# Generated by FakeRAM 2.0 (routing-friendly)
VERSION 5.7 ;
BUSBITCHARS "[]" ;
PROPERTYDEFINITIONS
  MACRO width INTEGER ;
  MACRO depth INTEGER ;
  MACRO banks INTEGER ;
END PROPERTYDEFINITIONS
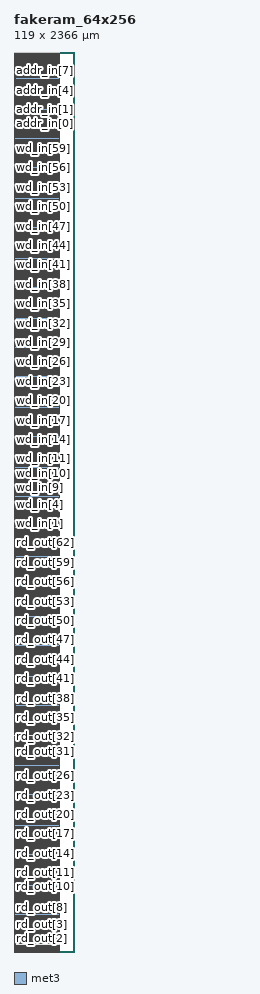
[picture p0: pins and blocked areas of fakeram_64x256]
MACRO fakeram_64x256
  PROPERTY width 64 ;
  PROPERTY depth 256 ;
  PROPERTY banks 1 ;
  FOREIGN fakeram_64x256 0 0 ;
  SYMMETRY X Y R90 ;
  SIZE 119.000 BY 2366.000 ;
  CLASS BLOCK ;
  PIN rd_out[0]
    DIRECTION OUTPUT ;
    USE SIGNAL ;
    PORT
      LAYER met3 ;
      RECT 1.000 0.680 3.000 1.380 ;
    END
    PORT
      LAYER met3 ;
      RECT 1.000 0.330 4.000 1.730 ;
    END
  END rd_out[0]
  PIN rd_out[1]
    DIRECTION OUTPUT ;
    USE SIGNAL ;
    PORT
      LAYER met3 ;
      RECT 1.000 17.680 3.000 18.380 ;
    END
    PORT
      LAYER met3 ;
      RECT 1.000 17.330 4.000 18.730 ;
    END
  END rd_out[1]
  PIN rd_out[2]
    DIRECTION OUTPUT ;
    USE SIGNAL ;
    PORT
      LAYER met3 ;
      RECT 1.000 34.680 3.000 35.380 ;
    END
    PORT
      LAYER met3 ;
      RECT 1.000 34.330 4.000 35.730 ;
    END
  END rd_out[2]
  PIN rd_out[3]
    DIRECTION OUTPUT ;
    USE SIGNAL ;
    PORT
      LAYER met3 ;
      RECT 1.000 51.680 3.000 52.380 ;
    END
    PORT
      LAYER met3 ;
      RECT 1.000 51.330 4.000 52.730 ;
    END
  END rd_out[3]
  PIN rd_out[4]
    DIRECTION OUTPUT ;
    USE SIGNAL ;
    PORT
      LAYER met3 ;
      RECT 1.000 68.680 3.000 69.380 ;
    END
    PORT
      LAYER met3 ;
      RECT 1.000 68.330 4.000 69.730 ;
    END
  END rd_out[4]
  PIN rd_out[5]
    DIRECTION OUTPUT ;
    USE SIGNAL ;
    PORT
      LAYER met3 ;
      RECT 1.000 85.680 3.000 86.380 ;
    END
    PORT
      LAYER met3 ;
      RECT 1.000 85.330 4.000 86.730 ;
    END
  END rd_out[5]
  PIN rd_out[6]
    DIRECTION OUTPUT ;
    USE SIGNAL ;
    PORT
      LAYER met3 ;
      RECT 1.000 102.680 3.000 103.380 ;
    END
    PORT
      LAYER met3 ;
      RECT 1.000 102.330 4.000 103.730 ;
    END
  END rd_out[6]
  PIN rd_out[7]
    DIRECTION OUTPUT ;
    USE SIGNAL ;
    PORT
      LAYER met3 ;
      RECT 1.000 119.680 3.000 120.380 ;
    END
    PORT
      LAYER met3 ;
      RECT 1.000 119.330 4.000 120.730 ;
    END
  END rd_out[7]
  PIN rd_out[8]
    DIRECTION OUTPUT ;
    USE SIGNAL ;
    PORT
      LAYER met3 ;
      RECT 1.000 136.680 3.000 137.380 ;
    END
    PORT
      LAYER met3 ;
      RECT 1.000 136.330 4.000 137.730 ;
    END
  END rd_out[8]
  PIN rd_out[9]
    DIRECTION OUTPUT ;
    USE SIGNAL ;
    PORT
      LAYER met3 ;
      RECT 1.000 153.680 3.000 154.380 ;
    END
    PORT
      LAYER met3 ;
      RECT 1.000 153.330 4.000 154.730 ;
    END
  END rd_out[9]
  PIN rd_out[10]
    DIRECTION OUTPUT ;
    USE SIGNAL ;
    PORT
      LAYER met3 ;
      RECT 1.000 170.680 3.000 171.380 ;
    END
    PORT
      LAYER met3 ;
      RECT 1.000 170.330 4.000 171.730 ;
    END
  END rd_out[10]
  PIN rd_out[11]
    DIRECTION OUTPUT ;
    USE SIGNAL ;
    PORT
      LAYER met3 ;
      RECT 1.000 187.680 3.000 188.380 ;
    END
    PORT
      LAYER met3 ;
      RECT 1.000 187.330 4.000 188.730 ;
    END
  END rd_out[11]
  PIN rd_out[12]
    DIRECTION OUTPUT ;
    USE SIGNAL ;
    PORT
      LAYER met3 ;
      RECT 1.000 204.680 3.000 205.380 ;
    END
    PORT
      LAYER met3 ;
      RECT 1.000 204.330 4.000 205.730 ;
    END
  END rd_out[12]
  PIN rd_out[13]
    DIRECTION OUTPUT ;
    USE SIGNAL ;
    PORT
      LAYER met3 ;
      RECT 1.000 221.680 3.000 222.380 ;
    END
    PORT
      LAYER met3 ;
      RECT 1.000 221.330 4.000 222.730 ;
    END
  END rd_out[13]
  PIN rd_out[14]
    DIRECTION OUTPUT ;
    USE SIGNAL ;
    PORT
      LAYER met3 ;
      RECT 1.000 238.680 3.000 239.380 ;
    END
    PORT
      LAYER met3 ;
      RECT 1.000 238.330 4.000 239.730 ;
    END
  END rd_out[14]
  PIN rd_out[15]
    DIRECTION OUTPUT ;
    USE SIGNAL ;
    PORT
      LAYER met3 ;
      RECT 1.000 255.680 3.000 256.380 ;
    END
    PORT
      LAYER met3 ;
      RECT 1.000 255.330 4.000 256.730 ;
    END
  END rd_out[15]
  PIN rd_out[16]
    DIRECTION OUTPUT ;
    USE SIGNAL ;
    PORT
      LAYER met3 ;
      RECT 1.000 272.680 3.000 273.380 ;
    END
    PORT
      LAYER met3 ;
      RECT 1.000 272.330 4.000 273.730 ;
    END
  END rd_out[16]
  PIN rd_out[17]
    DIRECTION OUTPUT ;
    USE SIGNAL ;
    PORT
      LAYER met3 ;
      RECT 1.000 289.680 3.000 290.380 ;
    END
    PORT
      LAYER met3 ;
      RECT 1.000 289.330 4.000 290.730 ;
    END
  END rd_out[17]
  PIN rd_out[18]
    DIRECTION OUTPUT ;
    USE SIGNAL ;
    PORT
      LAYER met3 ;
      RECT 1.000 306.680 3.000 307.380 ;
    END
    PORT
      LAYER met3 ;
      RECT 1.000 306.330 4.000 307.730 ;
    END
  END rd_out[18]
  PIN rd_out[19]
    DIRECTION OUTPUT ;
    USE SIGNAL ;
    PORT
      LAYER met3 ;
      RECT 1.000 323.680 3.000 324.380 ;
    END
    PORT
      LAYER met3 ;
      RECT 1.000 323.330 4.000 324.730 ;
    END
  END rd_out[19]
  PIN rd_out[20]
    DIRECTION OUTPUT ;
    USE SIGNAL ;
    PORT
      LAYER met3 ;
      RECT 1.000 340.680 3.000 341.380 ;
    END
    PORT
      LAYER met3 ;
      RECT 1.000 340.330 4.000 341.730 ;
    END
  END rd_out[20]
  PIN rd_out[21]
    DIRECTION OUTPUT ;
    USE SIGNAL ;
    PORT
      LAYER met3 ;
      RECT 1.000 357.680 3.000 358.380 ;
    END
    PORT
      LAYER met3 ;
      RECT 1.000 357.330 4.000 358.730 ;
    END
  END rd_out[21]
  PIN rd_out[22]
    DIRECTION OUTPUT ;
    USE SIGNAL ;
    PORT
      LAYER met3 ;
      RECT 1.000 374.680 3.000 375.380 ;
    END
    PORT
      LAYER met3 ;
      RECT 1.000 374.330 4.000 375.730 ;
    END
  END rd_out[22]
  PIN rd_out[23]
    DIRECTION OUTPUT ;
    USE SIGNAL ;
    PORT
      LAYER met3 ;
      RECT 1.000 391.680 3.000 392.380 ;
    END
    PORT
      LAYER met3 ;
      RECT 1.000 391.330 4.000 392.730 ;
    END
  END rd_out[23]
  PIN rd_out[24]
    DIRECTION OUTPUT ;
    USE SIGNAL ;
    PORT
      LAYER met3 ;
      RECT 1.000 408.680 3.000 409.380 ;
    END
    PORT
      LAYER met3 ;
      RECT 1.000 408.330 4.000 409.730 ;
    END
  END rd_out[24]
  PIN rd_out[25]
    DIRECTION OUTPUT ;
    USE SIGNAL ;
    PORT
      LAYER met3 ;
      RECT 1.000 425.680 3.000 426.380 ;
    END
    PORT
      LAYER met3 ;
      RECT 1.000 425.330 4.000 426.730 ;
    END
  END rd_out[25]
  PIN rd_out[26]
    DIRECTION OUTPUT ;
    USE SIGNAL ;
    PORT
      LAYER met3 ;
      RECT 1.000 442.680 3.000 443.380 ;
    END
    PORT
      LAYER met3 ;
      RECT 1.000 442.330 4.000 443.730 ;
    END
  END rd_out[26]
  PIN rd_out[27]
    DIRECTION OUTPUT ;
    USE SIGNAL ;
    PORT
      LAYER met3 ;
      RECT 1.000 459.680 3.000 460.380 ;
    END
    PORT
      LAYER met3 ;
      RECT 1.000 459.330 4.000 460.730 ;
    END
  END rd_out[27]
  PIN rd_out[28]
    DIRECTION OUTPUT ;
    USE SIGNAL ;
    PORT
      LAYER met3 ;
      RECT 1.000 476.680 3.000 477.380 ;
    END
    PORT
      LAYER met3 ;
      RECT 1.000 476.330 4.000 477.730 ;
    END
  END rd_out[28]
  PIN rd_out[29]
    DIRECTION OUTPUT ;
    USE SIGNAL ;
    PORT
      LAYER met3 ;
      RECT 1.000 493.680 3.000 494.380 ;
    END
    PORT
      LAYER met3 ;
      RECT 1.000 493.330 4.000 494.730 ;
    END
  END rd_out[29]
  PIN rd_out[30]
    DIRECTION OUTPUT ;
    USE SIGNAL ;
    PORT
      LAYER met3 ;
      RECT 1.000 510.680 3.000 511.380 ;
    END
    PORT
      LAYER met3 ;
      RECT 1.000 510.330 4.000 511.730 ;
    END
  END rd_out[30]
  PIN rd_out[31]
    DIRECTION OUTPUT ;
    USE SIGNAL ;
    PORT
      LAYER met3 ;
      RECT 1.000 527.680 3.000 528.380 ;
    END
    PORT
      LAYER met3 ;
      RECT 1.000 527.330 4.000 528.730 ;
    END
  END rd_out[31]
  PIN rd_out[32]
    DIRECTION OUTPUT ;
    USE SIGNAL ;
    PORT
      LAYER met3 ;
      RECT 1.000 544.680 3.000 545.380 ;
    END
    PORT
      LAYER met3 ;
      RECT 1.000 544.330 4.000 545.730 ;
    END
  END rd_out[32]
  PIN rd_out[33]
    DIRECTION OUTPUT ;
    USE SIGNAL ;
    PORT
      LAYER met3 ;
      RECT 1.000 561.680 3.000 562.380 ;
    END
    PORT
      LAYER met3 ;
      RECT 1.000 561.330 4.000 562.730 ;
    END
  END rd_out[33]
  PIN rd_out[34]
    DIRECTION OUTPUT ;
    USE SIGNAL ;
    PORT
      LAYER met3 ;
      RECT 1.000 578.680 3.000 579.380 ;
    END
    PORT
      LAYER met3 ;
      RECT 1.000 578.330 4.000 579.730 ;
    END
  END rd_out[34]
  PIN rd_out[35]
    DIRECTION OUTPUT ;
    USE SIGNAL ;
    PORT
      LAYER met3 ;
      RECT 1.000 595.680 3.000 596.380 ;
    END
    PORT
      LAYER met3 ;
      RECT 1.000 595.330 4.000 596.730 ;
    END
  END rd_out[35]
  PIN rd_out[36]
    DIRECTION OUTPUT ;
    USE SIGNAL ;
    PORT
      LAYER met3 ;
      RECT 1.000 612.680 3.000 613.380 ;
    END
    PORT
      LAYER met3 ;
      RECT 1.000 612.330 4.000 613.730 ;
    END
  END rd_out[36]
  PIN rd_out[37]
    DIRECTION OUTPUT ;
    USE SIGNAL ;
    PORT
      LAYER met3 ;
      RECT 1.000 629.680 3.000 630.380 ;
    END
    PORT
      LAYER met3 ;
      RECT 1.000 629.330 4.000 630.730 ;
    END
  END rd_out[37]
  PIN rd_out[38]
    DIRECTION OUTPUT ;
    USE SIGNAL ;
    PORT
      LAYER met3 ;
      RECT 1.000 646.680 3.000 647.380 ;
    END
    PORT
      LAYER met3 ;
      RECT 1.000 646.330 4.000 647.730 ;
    END
  END rd_out[38]
  PIN rd_out[39]
    DIRECTION OUTPUT ;
    USE SIGNAL ;
    PORT
      LAYER met3 ;
      RECT 1.000 663.680 3.000 664.380 ;
    END
    PORT
      LAYER met3 ;
      RECT 1.000 663.330 4.000 664.730 ;
    END
  END rd_out[39]
  PIN rd_out[40]
    DIRECTION OUTPUT ;
    USE SIGNAL ;
    PORT
      LAYER met3 ;
      RECT 1.000 680.680 3.000 681.380 ;
    END
    PORT
      LAYER met3 ;
      RECT 1.000 680.330 4.000 681.730 ;
    END
  END rd_out[40]
  PIN rd_out[41]
    DIRECTION OUTPUT ;
    USE SIGNAL ;
    PORT
      LAYER met3 ;
      RECT 1.000 697.680 3.000 698.380 ;
    END
    PORT
      LAYER met3 ;
      RECT 1.000 697.330 4.000 698.730 ;
    END
  END rd_out[41]
  PIN rd_out[42]
    DIRECTION OUTPUT ;
    USE SIGNAL ;
    PORT
      LAYER met3 ;
      RECT 1.000 714.680 3.000 715.380 ;
    END
    PORT
      LAYER met3 ;
      RECT 1.000 714.330 4.000 715.730 ;
    END
  END rd_out[42]
  PIN rd_out[43]
    DIRECTION OUTPUT ;
    USE SIGNAL ;
    PORT
      LAYER met3 ;
      RECT 1.000 731.680 3.000 732.380 ;
    END
    PORT
      LAYER met3 ;
      RECT 1.000 731.330 4.000 732.730 ;
    END
  END rd_out[43]
  PIN rd_out[44]
    DIRECTION OUTPUT ;
    USE SIGNAL ;
    PORT
      LAYER met3 ;
      RECT 1.000 748.680 3.000 749.380 ;
    END
    PORT
      LAYER met3 ;
      RECT 1.000 748.330 4.000 749.730 ;
    END
  END rd_out[44]
  PIN rd_out[45]
    DIRECTION OUTPUT ;
    USE SIGNAL ;
    PORT
      LAYER met3 ;
      RECT 1.000 765.680 3.000 766.380 ;
    END
    PORT
      LAYER met3 ;
      RECT 1.000 765.330 4.000 766.730 ;
    END
  END rd_out[45]
  PIN rd_out[46]
    DIRECTION OUTPUT ;
    USE SIGNAL ;
    PORT
      LAYER met3 ;
      RECT 1.000 782.680 3.000 783.380 ;
    END
    PORT
      LAYER met3 ;
      RECT 1.000 782.330 4.000 783.730 ;
    END
  END rd_out[46]
  PIN rd_out[47]
    DIRECTION OUTPUT ;
    USE SIGNAL ;
    PORT
      LAYER met3 ;
      RECT 1.000 799.680 3.000 800.380 ;
    END
    PORT
      LAYER met3 ;
      RECT 1.000 799.330 4.000 800.730 ;
    END
  END rd_out[47]
  PIN rd_out[48]
    DIRECTION OUTPUT ;
    USE SIGNAL ;
    PORT
      LAYER met3 ;
      RECT 1.000 816.680 3.000 817.380 ;
    END
    PORT
      LAYER met3 ;
      RECT 1.000 816.330 4.000 817.730 ;
    END
  END rd_out[48]
  PIN rd_out[49]
    DIRECTION OUTPUT ;
    USE SIGNAL ;
    PORT
      LAYER met3 ;
      RECT 1.000 833.680 3.000 834.380 ;
    END
    PORT
      LAYER met3 ;
      RECT 1.000 833.330 4.000 834.730 ;
    END
  END rd_out[49]
  PIN rd_out[50]
    DIRECTION OUTPUT ;
    USE SIGNAL ;
    PORT
      LAYER met3 ;
      RECT 1.000 850.680 3.000 851.380 ;
    END
    PORT
      LAYER met3 ;
      RECT 1.000 850.330 4.000 851.730 ;
    END
  END rd_out[50]
  PIN rd_out[51]
    DIRECTION OUTPUT ;
    USE SIGNAL ;
    PORT
      LAYER met3 ;
      RECT 1.000 867.680 3.000 868.380 ;
    END
    PORT
      LAYER met3 ;
      RECT 1.000 867.330 4.000 868.730 ;
    END
  END rd_out[51]
  PIN rd_out[52]
    DIRECTION OUTPUT ;
    USE SIGNAL ;
    PORT
      LAYER met3 ;
      RECT 1.000 884.680 3.000 885.380 ;
    END
    PORT
      LAYER met3 ;
      RECT 1.000 884.330 4.000 885.730 ;
    END
  END rd_out[52]
  PIN rd_out[53]
    DIRECTION OUTPUT ;
    USE SIGNAL ;
    PORT
      LAYER met3 ;
      RECT 1.000 901.680 3.000 902.380 ;
    END
    PORT
      LAYER met3 ;
      RECT 1.000 901.330 4.000 902.730 ;
    END
  END rd_out[53]
  PIN rd_out[54]
    DIRECTION OUTPUT ;
    USE SIGNAL ;
    PORT
      LAYER met3 ;
      RECT 1.000 918.680 3.000 919.380 ;
    END
    PORT
      LAYER met3 ;
      RECT 1.000 918.330 4.000 919.730 ;
    END
  END rd_out[54]
  PIN rd_out[55]
    DIRECTION OUTPUT ;
    USE SIGNAL ;
    PORT
      LAYER met3 ;
      RECT 1.000 935.680 3.000 936.380 ;
    END
    PORT
      LAYER met3 ;
      RECT 1.000 935.330 4.000 936.730 ;
    END
  END rd_out[55]
  PIN rd_out[56]
    DIRECTION OUTPUT ;
    USE SIGNAL ;
    PORT
      LAYER met3 ;
      RECT 1.000 952.680 3.000 953.380 ;
    END
    PORT
      LAYER met3 ;
      RECT 1.000 952.330 4.000 953.730 ;
    END
  END rd_out[56]
  PIN rd_out[57]
    DIRECTION OUTPUT ;
    USE SIGNAL ;
    PORT
      LAYER met3 ;
      RECT 1.000 969.680 3.000 970.380 ;
    END
    PORT
      LAYER met3 ;
      RECT 1.000 969.330 4.000 970.730 ;
    END
  END rd_out[57]
  PIN rd_out[58]
    DIRECTION OUTPUT ;
    USE SIGNAL ;
    PORT
      LAYER met3 ;
      RECT 1.000 986.680 3.000 987.380 ;
    END
    PORT
      LAYER met3 ;
      RECT 1.000 986.330 4.000 987.730 ;
    END
  END rd_out[58]
  PIN rd_out[59]
    DIRECTION OUTPUT ;
    USE SIGNAL ;
    PORT
      LAYER met3 ;
      RECT 1.000 1003.680 3.000 1004.380 ;
    END
    PORT
      LAYER met3 ;
      RECT 1.000 1003.330 4.000 1004.730 ;
    END
  END rd_out[59]
  PIN rd_out[60]
    DIRECTION OUTPUT ;
    USE SIGNAL ;
    PORT
      LAYER met3 ;
      RECT 1.000 1020.680 3.000 1021.380 ;
    END
    PORT
      LAYER met3 ;
      RECT 1.000 1020.330 4.000 1021.730 ;
    END
  END rd_out[60]
  PIN rd_out[61]
    DIRECTION OUTPUT ;
    USE SIGNAL ;
    PORT
      LAYER met3 ;
      RECT 1.000 1037.680 3.000 1038.380 ;
    END
    PORT
      LAYER met3 ;
      RECT 1.000 1037.330 4.000 1038.730 ;
    END
  END rd_out[61]
  PIN rd_out[62]
    DIRECTION OUTPUT ;
    USE SIGNAL ;
    PORT
      LAYER met3 ;
      RECT 1.000 1054.680 3.000 1055.380 ;
    END
    PORT
      LAYER met3 ;
      RECT 1.000 1054.330 4.000 1055.730 ;
    END
  END rd_out[62]
  PIN rd_out[63]
    DIRECTION OUTPUT ;
    USE SIGNAL ;
    PORT
      LAYER met3 ;
      RECT 1.000 1071.680 3.000 1072.380 ;
    END
    PORT
      LAYER met3 ;
      RECT 1.000 1071.330 4.000 1072.730 ;
    END
  END rd_out[63]
  PIN wd_in[0]
    DIRECTION INPUT ;
    USE SIGNAL ;
    PORT
      LAYER met3 ;
      RECT 1.000 1088.680 3.000 1089.380 ;
    END
    PORT
      LAYER met3 ;
      RECT 1.000 1088.330 4.000 1089.730 ;
    END
  END wd_in[0]
  PIN wd_in[1]
    DIRECTION INPUT ;
    USE SIGNAL ;
    PORT
      LAYER met3 ;
      RECT 1.000 1105.680 3.000 1106.380 ;
    END
    PORT
      LAYER met3 ;
      RECT 1.000 1105.330 4.000 1106.730 ;
    END
  END wd_in[1]
  PIN wd_in[2]
    DIRECTION INPUT ;
    USE SIGNAL ;
    PORT
      LAYER met3 ;
      RECT 1.000 1122.680 3.000 1123.380 ;
    END
    PORT
      LAYER met3 ;
      RECT 1.000 1122.330 4.000 1123.730 ;
    END
  END wd_in[2]
  PIN wd_in[3]
    DIRECTION INPUT ;
    USE SIGNAL ;
    PORT
      LAYER met3 ;
      RECT 1.000 1139.680 3.000 1140.380 ;
    END
    PORT
      LAYER met3 ;
      RECT 1.000 1139.330 4.000 1140.730 ;
    END
  END wd_in[3]
  PIN wd_in[4]
    DIRECTION INPUT ;
    USE SIGNAL ;
    PORT
      LAYER met3 ;
      RECT 1.000 1156.680 3.000 1157.380 ;
    END
    PORT
      LAYER met3 ;
      RECT 1.000 1156.330 4.000 1157.730 ;
    END
  END wd_in[4]
  PIN wd_in[5]
    DIRECTION INPUT ;
    USE SIGNAL ;
    PORT
      LAYER met3 ;
      RECT 1.000 1173.680 3.000 1174.380 ;
    END
    PORT
      LAYER met3 ;
      RECT 1.000 1173.330 4.000 1174.730 ;
    END
  END wd_in[5]
  PIN wd_in[6]
    DIRECTION INPUT ;
    USE SIGNAL ;
    PORT
      LAYER met3 ;
      RECT 1.000 1190.680 3.000 1191.380 ;
    END
    PORT
      LAYER met3 ;
      RECT 1.000 1190.330 4.000 1191.730 ;
    END
  END wd_in[6]
  PIN wd_in[7]
    DIRECTION INPUT ;
    USE SIGNAL ;
    PORT
      LAYER met3 ;
      RECT 1.000 1207.680 3.000 1208.380 ;
    END
    PORT
      LAYER met3 ;
      RECT 1.000 1207.330 4.000 1208.730 ;
    END
  END wd_in[7]
  PIN wd_in[8]
    DIRECTION INPUT ;
    USE SIGNAL ;
    PORT
      LAYER met3 ;
      RECT 1.000 1224.680 3.000 1225.380 ;
    END
    PORT
      LAYER met3 ;
      RECT 1.000 1224.330 4.000 1225.730 ;
    END
  END wd_in[8]
  PIN wd_in[9]
    DIRECTION INPUT ;
    USE SIGNAL ;
    PORT
      LAYER met3 ;
      RECT 1.000 1241.680 3.000 1242.380 ;
    END
    PORT
      LAYER met3 ;
      RECT 1.000 1241.330 4.000 1242.730 ;
    END
  END wd_in[9]
  PIN wd_in[10]
    DIRECTION INPUT ;
    USE SIGNAL ;
    PORT
      LAYER met3 ;
      RECT 1.000 1258.680 3.000 1259.380 ;
    END
    PORT
      LAYER met3 ;
      RECT 1.000 1258.330 4.000 1259.730 ;
    END
  END wd_in[10]
  PIN wd_in[11]
    DIRECTION INPUT ;
    USE SIGNAL ;
    PORT
      LAYER met3 ;
      RECT 1.000 1275.680 3.000 1276.380 ;
    END
    PORT
      LAYER met3 ;
      RECT 1.000 1275.330 4.000 1276.730 ;
    END
  END wd_in[11]
  PIN wd_in[12]
    DIRECTION INPUT ;
    USE SIGNAL ;
    PORT
      LAYER met3 ;
      RECT 1.000 1292.680 3.000 1293.380 ;
    END
    PORT
      LAYER met3 ;
      RECT 1.000 1292.330 4.000 1293.730 ;
    END
  END wd_in[12]
  PIN wd_in[13]
    DIRECTION INPUT ;
    USE SIGNAL ;
    PORT
      LAYER met3 ;
      RECT 1.000 1309.680 3.000 1310.380 ;
    END
    PORT
      LAYER met3 ;
      RECT 1.000 1309.330 4.000 1310.730 ;
    END
  END wd_in[13]
  PIN wd_in[14]
    DIRECTION INPUT ;
    USE SIGNAL ;
    PORT
      LAYER met3 ;
      RECT 1.000 1326.680 3.000 1327.380 ;
    END
    PORT
      LAYER met3 ;
      RECT 1.000 1326.330 4.000 1327.730 ;
    END
  END wd_in[14]
  PIN wd_in[15]
    DIRECTION INPUT ;
    USE SIGNAL ;
    PORT
      LAYER met3 ;
      RECT 1.000 1343.680 3.000 1344.380 ;
    END
    PORT
      LAYER met3 ;
      RECT 1.000 1343.330 4.000 1344.730 ;
    END
  END wd_in[15]
  PIN wd_in[16]
    DIRECTION INPUT ;
    USE SIGNAL ;
    PORT
      LAYER met3 ;
      RECT 1.000 1360.680 3.000 1361.380 ;
    END
    PORT
      LAYER met3 ;
      RECT 1.000 1360.330 4.000 1361.730 ;
    END
  END wd_in[16]
  PIN wd_in[17]
    DIRECTION INPUT ;
    USE SIGNAL ;
    PORT
      LAYER met3 ;
      RECT 1.000 1377.680 3.000 1378.380 ;
    END
    PORT
      LAYER met3 ;
      RECT 1.000 1377.330 4.000 1378.730 ;
    END
  END wd_in[17]
  PIN wd_in[18]
    DIRECTION INPUT ;
    USE SIGNAL ;
    PORT
      LAYER met3 ;
      RECT 1.000 1394.680 3.000 1395.380 ;
    END
    PORT
      LAYER met3 ;
      RECT 1.000 1394.330 4.000 1395.730 ;
    END
  END wd_in[18]
  PIN wd_in[19]
    DIRECTION INPUT ;
    USE SIGNAL ;
    PORT
      LAYER met3 ;
      RECT 1.000 1411.680 3.000 1412.380 ;
    END
    PORT
      LAYER met3 ;
      RECT 1.000 1411.330 4.000 1412.730 ;
    END
  END wd_in[19]
  PIN wd_in[20]
    DIRECTION INPUT ;
    USE SIGNAL ;
    PORT
      LAYER met3 ;
      RECT 1.000 1428.680 3.000 1429.380 ;
    END
    PORT
      LAYER met3 ;
      RECT 1.000 1428.330 4.000 1429.730 ;
    END
  END wd_in[20]
  PIN wd_in[21]
    DIRECTION INPUT ;
    USE SIGNAL ;
    PORT
      LAYER met3 ;
      RECT 1.000 1445.680 3.000 1446.380 ;
    END
    PORT
      LAYER met3 ;
      RECT 1.000 1445.330 4.000 1446.730 ;
    END
  END wd_in[21]
  PIN wd_in[22]
    DIRECTION INPUT ;
    USE SIGNAL ;
    PORT
      LAYER met3 ;
      RECT 1.000 1462.680 3.000 1463.380 ;
    END
    PORT
      LAYER met3 ;
      RECT 1.000 1462.330 4.000 1463.730 ;
    END
  END wd_in[22]
  PIN wd_in[23]
    DIRECTION INPUT ;
    USE SIGNAL ;
    PORT
      LAYER met3 ;
      RECT 1.000 1479.680 3.000 1480.380 ;
    END
    PORT
      LAYER met3 ;
      RECT 1.000 1479.330 4.000 1480.730 ;
    END
  END wd_in[23]
  PIN wd_in[24]
    DIRECTION INPUT ;
    USE SIGNAL ;
    PORT
      LAYER met3 ;
      RECT 1.000 1496.680 3.000 1497.380 ;
    END
    PORT
      LAYER met3 ;
      RECT 1.000 1496.330 4.000 1497.730 ;
    END
  END wd_in[24]
  PIN wd_in[25]
    DIRECTION INPUT ;
    USE SIGNAL ;
    PORT
      LAYER met3 ;
      RECT 1.000 1513.680 3.000 1514.380 ;
    END
    PORT
      LAYER met3 ;
      RECT 1.000 1513.330 4.000 1514.730 ;
    END
  END wd_in[25]
  PIN wd_in[26]
    DIRECTION INPUT ;
    USE SIGNAL ;
    PORT
      LAYER met3 ;
      RECT 1.000 1530.680 3.000 1531.380 ;
    END
    PORT
      LAYER met3 ;
      RECT 1.000 1530.330 4.000 1531.730 ;
    END
  END wd_in[26]
  PIN wd_in[27]
    DIRECTION INPUT ;
    USE SIGNAL ;
    PORT
      LAYER met3 ;
      RECT 1.000 1547.680 3.000 1548.380 ;
    END
    PORT
      LAYER met3 ;
      RECT 1.000 1547.330 4.000 1548.730 ;
    END
  END wd_in[27]
  PIN wd_in[28]
    DIRECTION INPUT ;
    USE SIGNAL ;
    PORT
      LAYER met3 ;
      RECT 1.000 1564.680 3.000 1565.380 ;
    END
    PORT
      LAYER met3 ;
      RECT 1.000 1564.330 4.000 1565.730 ;
    END
  END wd_in[28]
  PIN wd_in[29]
    DIRECTION INPUT ;
    USE SIGNAL ;
    PORT
      LAYER met3 ;
      RECT 1.000 1581.680 3.000 1582.380 ;
    END
    PORT
      LAYER met3 ;
      RECT 1.000 1581.330 4.000 1582.730 ;
    END
  END wd_in[29]
  PIN wd_in[30]
    DIRECTION INPUT ;
    USE SIGNAL ;
    PORT
      LAYER met3 ;
      RECT 1.000 1598.680 3.000 1599.380 ;
    END
    PORT
      LAYER met3 ;
      RECT 1.000 1598.330 4.000 1599.730 ;
    END
  END wd_in[30]
  PIN wd_in[31]
    DIRECTION INPUT ;
    USE SIGNAL ;
    PORT
      LAYER met3 ;
      RECT 1.000 1615.680 3.000 1616.380 ;
    END
    PORT
      LAYER met3 ;
      RECT 1.000 1615.330 4.000 1616.730 ;
    END
  END wd_in[31]
  PIN wd_in[32]
    DIRECTION INPUT ;
    USE SIGNAL ;
    PORT
      LAYER met3 ;
      RECT 1.000 1632.680 3.000 1633.380 ;
    END
    PORT
      LAYER met3 ;
      RECT 1.000 1632.330 4.000 1633.730 ;
    END
  END wd_in[32]
  PIN wd_in[33]
    DIRECTION INPUT ;
    USE SIGNAL ;
    PORT
      LAYER met3 ;
      RECT 1.000 1649.680 3.000 1650.380 ;
    END
    PORT
      LAYER met3 ;
      RECT 1.000 1649.330 4.000 1650.730 ;
    END
  END wd_in[33]
  PIN wd_in[34]
    DIRECTION INPUT ;
    USE SIGNAL ;
    PORT
      LAYER met3 ;
      RECT 1.000 1666.680 3.000 1667.380 ;
    END
    PORT
      LAYER met3 ;
      RECT 1.000 1666.330 4.000 1667.730 ;
    END
  END wd_in[34]
  PIN wd_in[35]
    DIRECTION INPUT ;
    USE SIGNAL ;
    PORT
      LAYER met3 ;
      RECT 1.000 1683.680 3.000 1684.380 ;
    END
    PORT
      LAYER met3 ;
      RECT 1.000 1683.330 4.000 1684.730 ;
    END
  END wd_in[35]
  PIN wd_in[36]
    DIRECTION INPUT ;
    USE SIGNAL ;
    PORT
      LAYER met3 ;
      RECT 1.000 1700.680 3.000 1701.380 ;
    END
    PORT
      LAYER met3 ;
      RECT 1.000 1700.330 4.000 1701.730 ;
    END
  END wd_in[36]
  PIN wd_in[37]
    DIRECTION INPUT ;
    USE SIGNAL ;
    PORT
      LAYER met3 ;
      RECT 1.000 1717.680 3.000 1718.380 ;
    END
    PORT
      LAYER met3 ;
      RECT 1.000 1717.330 4.000 1718.730 ;
    END
  END wd_in[37]
  PIN wd_in[38]
    DIRECTION INPUT ;
    USE SIGNAL ;
    PORT
      LAYER met3 ;
      RECT 1.000 1734.680 3.000 1735.380 ;
    END
    PORT
      LAYER met3 ;
      RECT 1.000 1734.330 4.000 1735.730 ;
    END
  END wd_in[38]
  PIN wd_in[39]
    DIRECTION INPUT ;
    USE SIGNAL ;
    PORT
      LAYER met3 ;
      RECT 1.000 1751.680 3.000 1752.380 ;
    END
    PORT
      LAYER met3 ;
      RECT 1.000 1751.330 4.000 1752.730 ;
    END
  END wd_in[39]
  PIN wd_in[40]
    DIRECTION INPUT ;
    USE SIGNAL ;
    PORT
      LAYER met3 ;
      RECT 1.000 1768.680 3.000 1769.380 ;
    END
    PORT
      LAYER met3 ;
      RECT 1.000 1768.330 4.000 1769.730 ;
    END
  END wd_in[40]
  PIN wd_in[41]
    DIRECTION INPUT ;
    USE SIGNAL ;
    PORT
      LAYER met3 ;
      RECT 1.000 1785.680 3.000 1786.380 ;
    END
    PORT
      LAYER met3 ;
      RECT 1.000 1785.330 4.000 1786.730 ;
    END
  END wd_in[41]
  PIN wd_in[42]
    DIRECTION INPUT ;
    USE SIGNAL ;
    PORT
      LAYER met3 ;
      RECT 1.000 1802.680 3.000 1803.380 ;
    END
    PORT
      LAYER met3 ;
      RECT 1.000 1802.330 4.000 1803.730 ;
    END
  END wd_in[42]
  PIN wd_in[43]
    DIRECTION INPUT ;
    USE SIGNAL ;
    PORT
      LAYER met3 ;
      RECT 1.000 1819.680 3.000 1820.380 ;
    END
    PORT
      LAYER met3 ;
      RECT 1.000 1819.330 4.000 1820.730 ;
    END
  END wd_in[43]
  PIN wd_in[44]
    DIRECTION INPUT ;
    USE SIGNAL ;
    PORT
      LAYER met3 ;
      RECT 1.000 1836.680 3.000 1837.380 ;
    END
    PORT
      LAYER met3 ;
      RECT 1.000 1836.330 4.000 1837.730 ;
    END
  END wd_in[44]
  PIN wd_in[45]
    DIRECTION INPUT ;
    USE SIGNAL ;
    PORT
      LAYER met3 ;
      RECT 1.000 1853.680 3.000 1854.380 ;
    END
    PORT
      LAYER met3 ;
      RECT 1.000 1853.330 4.000 1854.730 ;
    END
  END wd_in[45]
  PIN wd_in[46]
    DIRECTION INPUT ;
    USE SIGNAL ;
    PORT
      LAYER met3 ;
      RECT 1.000 1870.680 3.000 1871.380 ;
    END
    PORT
      LAYER met3 ;
      RECT 1.000 1870.330 4.000 1871.730 ;
    END
  END wd_in[46]
  PIN wd_in[47]
    DIRECTION INPUT ;
    USE SIGNAL ;
    PORT
      LAYER met3 ;
      RECT 1.000 1887.680 3.000 1888.380 ;
    END
    PORT
      LAYER met3 ;
      RECT 1.000 1887.330 4.000 1888.730 ;
    END
  END wd_in[47]
  PIN wd_in[48]
    DIRECTION INPUT ;
    USE SIGNAL ;
    PORT
      LAYER met3 ;
      RECT 1.000 1904.680 3.000 1905.380 ;
    END
    PORT
      LAYER met3 ;
      RECT 1.000 1904.330 4.000 1905.730 ;
    END
  END wd_in[48]
  PIN wd_in[49]
    DIRECTION INPUT ;
    USE SIGNAL ;
    PORT
      LAYER met3 ;
      RECT 1.000 1921.680 3.000 1922.380 ;
    END
    PORT
      LAYER met3 ;
      RECT 1.000 1921.330 4.000 1922.730 ;
    END
  END wd_in[49]
  PIN wd_in[50]
    DIRECTION INPUT ;
    USE SIGNAL ;
    PORT
      LAYER met3 ;
      RECT 1.000 1938.680 3.000 1939.380 ;
    END
    PORT
      LAYER met3 ;
      RECT 1.000 1938.330 4.000 1939.730 ;
    END
  END wd_in[50]
  PIN wd_in[51]
    DIRECTION INPUT ;
    USE SIGNAL ;
    PORT
      LAYER met3 ;
      RECT 1.000 1955.680 3.000 1956.380 ;
    END
    PORT
      LAYER met3 ;
      RECT 1.000 1955.330 4.000 1956.730 ;
    END
  END wd_in[51]
  PIN wd_in[52]
    DIRECTION INPUT ;
    USE SIGNAL ;
    PORT
      LAYER met3 ;
      RECT 1.000 1972.680 3.000 1973.380 ;
    END
    PORT
      LAYER met3 ;
      RECT 1.000 1972.330 4.000 1973.730 ;
    END
  END wd_in[52]
  PIN wd_in[53]
    DIRECTION INPUT ;
    USE SIGNAL ;
    PORT
      LAYER met3 ;
      RECT 1.000 1989.680 3.000 1990.380 ;
    END
    PORT
      LAYER met3 ;
      RECT 1.000 1989.330 4.000 1990.730 ;
    END
  END wd_in[53]
  PIN wd_in[54]
    DIRECTION INPUT ;
    USE SIGNAL ;
    PORT
      LAYER met3 ;
      RECT 1.000 2006.680 3.000 2007.380 ;
    END
    PORT
      LAYER met3 ;
      RECT 1.000 2006.330 4.000 2007.730 ;
    END
  END wd_in[54]
  PIN wd_in[55]
    DIRECTION INPUT ;
    USE SIGNAL ;
    PORT
      LAYER met3 ;
      RECT 1.000 2023.680 3.000 2024.380 ;
    END
    PORT
      LAYER met3 ;
      RECT 1.000 2023.330 4.000 2024.730 ;
    END
  END wd_in[55]
  PIN wd_in[56]
    DIRECTION INPUT ;
    USE SIGNAL ;
    PORT
      LAYER met3 ;
      RECT 1.000 2040.680 3.000 2041.380 ;
    END
    PORT
      LAYER met3 ;
      RECT 1.000 2040.330 4.000 2041.730 ;
    END
  END wd_in[56]
  PIN wd_in[57]
    DIRECTION INPUT ;
    USE SIGNAL ;
    PORT
      LAYER met3 ;
      RECT 1.000 2057.680 3.000 2058.380 ;
    END
    PORT
      LAYER met3 ;
      RECT 1.000 2057.330 4.000 2058.730 ;
    END
  END wd_in[57]
  PIN wd_in[58]
    DIRECTION INPUT ;
    USE SIGNAL ;
    PORT
      LAYER met3 ;
      RECT 1.000 2074.680 3.000 2075.380 ;
    END
    PORT
      LAYER met3 ;
      RECT 1.000 2074.330 4.000 2075.730 ;
    END
  END wd_in[58]
  PIN wd_in[59]
    DIRECTION INPUT ;
    USE SIGNAL ;
    PORT
      LAYER met3 ;
      RECT 1.000 2091.680 3.000 2092.380 ;
    END
    PORT
      LAYER met3 ;
      RECT 1.000 2091.330 4.000 2092.730 ;
    END
  END wd_in[59]
  PIN wd_in[60]
    DIRECTION INPUT ;
    USE SIGNAL ;
    PORT
      LAYER met3 ;
      RECT 1.000 2108.680 3.000 2109.380 ;
    END
    PORT
      LAYER met3 ;
      RECT 1.000 2108.330 4.000 2109.730 ;
    END
  END wd_in[60]
  PIN wd_in[61]
    DIRECTION INPUT ;
    USE SIGNAL ;
    PORT
      LAYER met3 ;
      RECT 1.000 2125.680 3.000 2126.380 ;
    END
    PORT
      LAYER met3 ;
      RECT 1.000 2125.330 4.000 2126.730 ;
    END
  END wd_in[61]
  PIN wd_in[62]
    DIRECTION INPUT ;
    USE SIGNAL ;
    PORT
      LAYER met3 ;
      RECT 1.000 2142.680 3.000 2143.380 ;
    END
    PORT
      LAYER met3 ;
      RECT 1.000 2142.330 4.000 2143.730 ;
    END
  END wd_in[62]
  PIN wd_in[63]
    DIRECTION INPUT ;
    USE SIGNAL ;
    PORT
      LAYER met3 ;
      RECT 1.000 2159.680 3.000 2160.380 ;
    END
    PORT
      LAYER met3 ;
      RECT 1.000 2159.330 4.000 2160.730 ;
    END
  END wd_in[63]
  PIN addr_in[0]
    DIRECTION INPUT ;
    USE SIGNAL ;
    PORT
      LAYER met3 ;
      RECT 1.000 2176.680 3.000 2177.380 ;
    END
    PORT
      LAYER met3 ;
      RECT 1.000 2176.330 4.000 2177.730 ;
    END
  END addr_in[0]
  PIN addr_in[1]
    DIRECTION INPUT ;
    USE SIGNAL ;
    PORT
      LAYER met3 ;
      RECT 1.000 2193.680 3.000 2194.380 ;
    END
    PORT
      LAYER met3 ;
      RECT 1.000 2193.330 4.000 2194.730 ;
    END
  END addr_in[1]
  PIN addr_in[2]
    DIRECTION INPUT ;
    USE SIGNAL ;
    PORT
      LAYER met3 ;
      RECT 1.000 2210.680 3.000 2211.380 ;
    END
    PORT
      LAYER met3 ;
      RECT 1.000 2210.330 4.000 2211.730 ;
    END
  END addr_in[2]
  PIN addr_in[3]
    DIRECTION INPUT ;
    USE SIGNAL ;
    PORT
      LAYER met3 ;
      RECT 1.000 2227.680 3.000 2228.380 ;
    END
    PORT
      LAYER met3 ;
      RECT 1.000 2227.330 4.000 2228.730 ;
    END
  END addr_in[3]
  PIN addr_in[4]
    DIRECTION INPUT ;
    USE SIGNAL ;
    PORT
      LAYER met3 ;
      RECT 1.000 2244.680 3.000 2245.380 ;
    END
    PORT
      LAYER met3 ;
      RECT 1.000 2244.330 4.000 2245.730 ;
    END
  END addr_in[4]
  PIN addr_in[5]
    DIRECTION INPUT ;
    USE SIGNAL ;
    PORT
      LAYER met3 ;
      RECT 1.000 2261.680 3.000 2262.380 ;
    END
    PORT
      LAYER met3 ;
      RECT 1.000 2261.330 4.000 2262.730 ;
    END
  END addr_in[5]
  PIN addr_in[6]
    DIRECTION INPUT ;
    USE SIGNAL ;
    PORT
      LAYER met3 ;
      RECT 1.000 2278.680 3.000 2279.380 ;
    END
    PORT
      LAYER met3 ;
      RECT 1.000 2278.330 4.000 2279.730 ;
    END
  END addr_in[6]
  PIN addr_in[7]
    DIRECTION INPUT ;
    USE SIGNAL ;
    PORT
      LAYER met3 ;
      RECT 1.000 2295.680 3.000 2296.380 ;
    END
    PORT
      LAYER met3 ;
      RECT 1.000 2295.330 4.000 2296.730 ;
    END
  END addr_in[7]
  PIN we_in
    DIRECTION INPUT ;
    USE SIGNAL ;
    PORT
      LAYER met3 ;
      RECT 1.000 2312.680 3.000 2313.380 ;
    END
    PORT
      LAYER met3 ;
      RECT 1.000 2312.330 4.000 2313.730 ;
    END
  END we_in
  PIN ce_in
    DIRECTION INPUT ;
    USE SIGNAL ;
    PORT
      LAYER met3 ;
      RECT 1.000 2329.680 3.000 2330.380 ;
    END
    PORT
      LAYER met3 ;
      RECT 1.000 2329.330 4.000 2330.730 ;
    END
  END ce_in
  PIN clk
    DIRECTION INPUT ;
    USE SIGNAL ;
    PORT
      LAYER met3 ;
      RECT 1.000 2346.680 3.000 2347.380 ;
    END
    PORT
      LAYER met3 ;
      RECT 1.000 2346.330 4.000 2347.730 ;
    END
  END clk
  PIN VSS
    DIRECTION INOUT ;
    USE GROUND ;
    PORT
      LAYER met3 ;
      RECT 0.680 -0.720 118.320 2.080 ;
      RECT 0.680 10.160 118.320 12.960 ;
      RECT 0.680 21.040 118.320 23.840 ;
      RECT 0.680 31.920 118.320 34.720 ;
      RECT 0.680 42.800 118.320 45.600 ;
      RECT 0.680 53.680 118.320 56.480 ;
      RECT 0.680 64.560 118.320 67.360 ;
      RECT 0.680 75.440 118.320 78.240 ;
      RECT 0.680 86.320 118.320 89.120 ;
      RECT 0.680 97.200 118.320 100.000 ;
      RECT 0.680 108.080 118.320 110.880 ;
      RECT 0.680 118.960 118.320 121.760 ;
      RECT 0.680 129.840 118.320 132.640 ;
      RECT 0.680 140.720 118.320 143.520 ;
      RECT 0.680 151.600 118.320 154.400 ;
      RECT 0.680 162.480 118.320 165.280 ;
      RECT 0.680 173.360 118.320 176.160 ;
      RECT 0.680 184.240 118.320 187.040 ;
      RECT 0.680 195.120 118.320 197.920 ;
      RECT 0.680 206.000 118.320 208.800 ;
      RECT 0.680 216.880 118.320 219.680 ;
      RECT 0.680 227.760 118.320 230.560 ;
      RECT 0.680 238.640 118.320 241.440 ;
      RECT 0.680 249.520 118.320 252.320 ;
      RECT 0.680 260.400 118.320 263.200 ;
      RECT 0.680 271.280 118.320 274.080 ;
      RECT 0.680 282.160 118.320 284.960 ;
      RECT 0.680 293.040 118.320 295.840 ;
      RECT 0.680 303.920 118.320 306.720 ;
      RECT 0.680 314.800 118.320 317.600 ;
      RECT 0.680 325.680 118.320 328.480 ;
      RECT 0.680 336.560 118.320 339.360 ;
      RECT 0.680 347.440 118.320 350.240 ;
      RECT 0.680 358.320 118.320 361.120 ;
      RECT 0.680 369.200 118.320 372.000 ;
      RECT 0.680 380.080 118.320 382.880 ;
      RECT 0.680 390.960 118.320 393.760 ;
      RECT 0.680 401.840 118.320 404.640 ;
      RECT 0.680 412.720 118.320 415.520 ;
      RECT 0.680 423.600 118.320 426.400 ;
      RECT 0.680 434.480 118.320 437.280 ;
      RECT 0.680 445.360 118.320 448.160 ;
      RECT 0.680 456.240 118.320 459.040 ;
      RECT 0.680 467.120 118.320 469.920 ;
      RECT 0.680 478.000 118.320 480.800 ;
      RECT 0.680 488.880 118.320 491.680 ;
      RECT 0.680 499.760 118.320 502.560 ;
      RECT 0.680 510.640 118.320 513.440 ;
      RECT 0.680 521.520 118.320 524.320 ;
      RECT 0.680 532.400 118.320 535.200 ;
      RECT 0.680 543.280 118.320 546.080 ;
      RECT 0.680 554.160 118.320 556.960 ;
      RECT 0.680 565.040 118.320 567.840 ;
      RECT 0.680 575.920 118.320 578.720 ;
      RECT 0.680 586.800 118.320 589.600 ;
      RECT 0.680 597.680 118.320 600.480 ;
      RECT 0.680 608.560 118.320 611.360 ;
      RECT 0.680 619.440 118.320 622.240 ;
      RECT 0.680 630.320 118.320 633.120 ;
      RECT 0.680 641.200 118.320 644.000 ;
      RECT 0.680 652.080 118.320 654.880 ;
      RECT 0.680 662.960 118.320 665.760 ;
      RECT 0.680 673.840 118.320 676.640 ;
      RECT 0.680 684.720 118.320 687.520 ;
      RECT 0.680 695.600 118.320 698.400 ;
      RECT 0.680 706.480 118.320 709.280 ;
      RECT 0.680 717.360 118.320 720.160 ;
      RECT 0.680 728.240 118.320 731.040 ;
      RECT 0.680 739.120 118.320 741.920 ;
      RECT 0.680 750.000 118.320 752.800 ;
      RECT 0.680 760.880 118.320 763.680 ;
      RECT 0.680 771.760 118.320 774.560 ;
      RECT 0.680 782.640 118.320 785.440 ;
      RECT 0.680 793.520 118.320 796.320 ;
      RECT 0.680 804.400 118.320 807.200 ;
      RECT 0.680 815.280 118.320 818.080 ;
      RECT 0.680 826.160 118.320 828.960 ;
      RECT 0.680 837.040 118.320 839.840 ;
      RECT 0.680 847.920 118.320 850.720 ;
      RECT 0.680 858.800 118.320 861.600 ;
      RECT 0.680 869.680 118.320 872.480 ;
      RECT 0.680 880.560 118.320 883.360 ;
      RECT 0.680 891.440 118.320 894.240 ;
      RECT 0.680 902.320 118.320 905.120 ;
      RECT 0.680 913.200 118.320 916.000 ;
      RECT 0.680 924.080 118.320 926.880 ;
      RECT 0.680 934.960 118.320 937.760 ;
      RECT 0.680 945.840 118.320 948.640 ;
      RECT 0.680 956.720 118.320 959.520 ;
      RECT 0.680 967.600 118.320 970.400 ;
      RECT 0.680 978.480 118.320 981.280 ;
      RECT 0.680 989.360 118.320 992.160 ;
      RECT 0.680 1000.240 118.320 1003.040 ;
      RECT 0.680 1011.120 118.320 1013.920 ;
      RECT 0.680 1022.000 118.320 1024.800 ;
      RECT 0.680 1032.880 118.320 1035.680 ;
      RECT 0.680 1043.760 118.320 1046.560 ;
      RECT 0.680 1054.640 118.320 1057.440 ;
      RECT 0.680 1065.520 118.320 1068.320 ;
      RECT 0.680 1076.400 118.320 1079.200 ;
      RECT 0.680 1087.280 118.320 1090.080 ;
      RECT 0.680 1098.160 118.320 1100.960 ;
      RECT 0.680 1109.040 118.320 1111.840 ;
      RECT 0.680 1119.920 118.320 1122.720 ;
      RECT 0.680 1130.800 118.320 1133.600 ;
      RECT 0.680 1141.680 118.320 1144.480 ;
      RECT 0.680 1152.560 118.320 1155.360 ;
      RECT 0.680 1163.440 118.320 1166.240 ;
      RECT 0.680 1174.320 118.320 1177.120 ;
      RECT 0.680 1185.200 118.320 1188.000 ;
      RECT 0.680 1196.080 118.320 1198.880 ;
      RECT 0.680 1206.960 118.320 1209.760 ;
      RECT 0.680 1217.840 118.320 1220.640 ;
      RECT 0.680 1228.720 118.320 1231.520 ;
      RECT 0.680 1239.600 118.320 1242.400 ;
      RECT 0.680 1250.480 118.320 1253.280 ;
      RECT 0.680 1261.360 118.320 1264.160 ;
      RECT 0.680 1272.240 118.320 1275.040 ;
      RECT 0.680 1283.120 118.320 1285.920 ;
      RECT 0.680 1294.000 118.320 1296.800 ;
      RECT 0.680 1304.880 118.320 1307.680 ;
      RECT 0.680 1315.760 118.320 1318.560 ;
      RECT 0.680 1326.640 118.320 1329.440 ;
      RECT 0.680 1337.520 118.320 1340.320 ;
      RECT 0.680 1348.400 118.320 1351.200 ;
      RECT 0.680 1359.280 118.320 1362.080 ;
      RECT 0.680 1370.160 118.320 1372.960 ;
      RECT 0.680 1381.040 118.320 1383.840 ;
      RECT 0.680 1391.920 118.320 1394.720 ;
      RECT 0.680 1402.800 118.320 1405.600 ;
      RECT 0.680 1413.680 118.320 1416.480 ;
      RECT 0.680 1424.560 118.320 1427.360 ;
      RECT 0.680 1435.440 118.320 1438.240 ;
      RECT 0.680 1446.320 118.320 1449.120 ;
      RECT 0.680 1457.200 118.320 1460.000 ;
      RECT 0.680 1468.080 118.320 1470.880 ;
      RECT 0.680 1478.960 118.320 1481.760 ;
      RECT 0.680 1489.840 118.320 1492.640 ;
      RECT 0.680 1500.720 118.320 1503.520 ;
      RECT 0.680 1511.600 118.320 1514.400 ;
      RECT 0.680 1522.480 118.320 1525.280 ;
      RECT 0.680 1533.360 118.320 1536.160 ;
      RECT 0.680 1544.240 118.320 1547.040 ;
      RECT 0.680 1555.120 118.320 1557.920 ;
      RECT 0.680 1566.000 118.320 1568.800 ;
      RECT 0.680 1576.880 118.320 1579.680 ;
      RECT 0.680 1587.760 118.320 1590.560 ;
      RECT 0.680 1598.640 118.320 1601.440 ;
      RECT 0.680 1609.520 118.320 1612.320 ;
      RECT 0.680 1620.400 118.320 1623.200 ;
      RECT 0.680 1631.280 118.320 1634.080 ;
      RECT 0.680 1642.160 118.320 1644.960 ;
      RECT 0.680 1653.040 118.320 1655.840 ;
      RECT 0.680 1663.920 118.320 1666.720 ;
      RECT 0.680 1674.800 118.320 1677.600 ;
      RECT 0.680 1685.680 118.320 1688.480 ;
      RECT 0.680 1696.560 118.320 1699.360 ;
      RECT 0.680 1707.440 118.320 1710.240 ;
      RECT 0.680 1718.320 118.320 1721.120 ;
      RECT 0.680 1729.200 118.320 1732.000 ;
      RECT 0.680 1740.080 118.320 1742.880 ;
      RECT 0.680 1750.960 118.320 1753.760 ;
      RECT 0.680 1761.840 118.320 1764.640 ;
      RECT 0.680 1772.720 118.320 1775.520 ;
      RECT 0.680 1783.600 118.320 1786.400 ;
      RECT 0.680 1794.480 118.320 1797.280 ;
      RECT 0.680 1805.360 118.320 1808.160 ;
      RECT 0.680 1816.240 118.320 1819.040 ;
      RECT 0.680 1827.120 118.320 1829.920 ;
      RECT 0.680 1838.000 118.320 1840.800 ;
      RECT 0.680 1848.880 118.320 1851.680 ;
      RECT 0.680 1859.760 118.320 1862.560 ;
      RECT 0.680 1870.640 118.320 1873.440 ;
      RECT 0.680 1881.520 118.320 1884.320 ;
      RECT 0.680 1892.400 118.320 1895.200 ;
      RECT 0.680 1903.280 118.320 1906.080 ;
      RECT 0.680 1914.160 118.320 1916.960 ;
      RECT 0.680 1925.040 118.320 1927.840 ;
      RECT 0.680 1935.920 118.320 1938.720 ;
      RECT 0.680 1946.800 118.320 1949.600 ;
      RECT 0.680 1957.680 118.320 1960.480 ;
      RECT 0.680 1968.560 118.320 1971.360 ;
      RECT 0.680 1979.440 118.320 1982.240 ;
      RECT 0.680 1990.320 118.320 1993.120 ;
      RECT 0.680 2001.200 118.320 2004.000 ;
      RECT 0.680 2012.080 118.320 2014.880 ;
      RECT 0.680 2022.960 118.320 2025.760 ;
      RECT 0.680 2033.840 118.320 2036.640 ;
      RECT 0.680 2044.720 118.320 2047.520 ;
      RECT 0.680 2055.600 118.320 2058.400 ;
      RECT 0.680 2066.480 118.320 2069.280 ;
      RECT 0.680 2077.360 118.320 2080.160 ;
      RECT 0.680 2088.240 118.320 2091.040 ;
      RECT 0.680 2099.120 118.320 2101.920 ;
      RECT 0.680 2110.000 118.320 2112.800 ;
      RECT 0.680 2120.880 118.320 2123.680 ;
      RECT 0.680 2131.760 118.320 2134.560 ;
      RECT 0.680 2142.640 118.320 2145.440 ;
      RECT 0.680 2153.520 118.320 2156.320 ;
      RECT 0.680 2164.400 118.320 2167.200 ;
      RECT 0.680 2175.280 118.320 2178.080 ;
      RECT 0.680 2186.160 118.320 2188.960 ;
      RECT 0.680 2197.040 118.320 2199.840 ;
      RECT 0.680 2207.920 118.320 2210.720 ;
      RECT 0.680 2218.800 118.320 2221.600 ;
      RECT 0.680 2229.680 118.320 2232.480 ;
      RECT 0.680 2240.560 118.320 2243.360 ;
      RECT 0.680 2251.440 118.320 2254.240 ;
      RECT 0.680 2262.320 118.320 2265.120 ;
      RECT 0.680 2273.200 118.320 2276.000 ;
      RECT 0.680 2284.080 118.320 2286.880 ;
      RECT 0.680 2294.960 118.320 2297.760 ;
      RECT 0.680 2305.840 118.320 2308.640 ;
      RECT 0.680 2316.720 118.320 2319.520 ;
      RECT 0.680 2327.600 118.320 2330.400 ;
      RECT 0.680 2338.480 118.320 2341.280 ;
      RECT 0.680 2349.360 118.320 2352.160 ;
      RECT 0.680 2360.240 118.320 2363.040 ;
    END
  END VSS
  PIN VDD
    DIRECTION INOUT ;
    USE POWER ;
    PORT
      LAYER met3 ;
      RECT 0.680 4.720 118.320 7.520 ;
      RECT 0.680 15.600 118.320 18.400 ;
      RECT 0.680 26.480 118.320 29.280 ;
      RECT 0.680 37.360 118.320 40.160 ;
      RECT 0.680 48.240 118.320 51.040 ;
      RECT 0.680 59.120 118.320 61.920 ;
      RECT 0.680 70.000 118.320 72.800 ;
      RECT 0.680 80.880 118.320 83.680 ;
      RECT 0.680 91.760 118.320 94.560 ;
      RECT 0.680 102.640 118.320 105.440 ;
      RECT 0.680 113.520 118.320 116.320 ;
      RECT 0.680 124.400 118.320 127.200 ;
      RECT 0.680 135.280 118.320 138.080 ;
      RECT 0.680 146.160 118.320 148.960 ;
      RECT 0.680 157.040 118.320 159.840 ;
      RECT 0.680 167.920 118.320 170.720 ;
      RECT 0.680 178.800 118.320 181.600 ;
      RECT 0.680 189.680 118.320 192.480 ;
      RECT 0.680 200.560 118.320 203.360 ;
      RECT 0.680 211.440 118.320 214.240 ;
      RECT 0.680 222.320 118.320 225.120 ;
      RECT 0.680 233.200 118.320 236.000 ;
      RECT 0.680 244.080 118.320 246.880 ;
      RECT 0.680 254.960 118.320 257.760 ;
      RECT 0.680 265.840 118.320 268.640 ;
      RECT 0.680 276.720 118.320 279.520 ;
      RECT 0.680 287.600 118.320 290.400 ;
      RECT 0.680 298.480 118.320 301.280 ;
      RECT 0.680 309.360 118.320 312.160 ;
      RECT 0.680 320.240 118.320 323.040 ;
      RECT 0.680 331.120 118.320 333.920 ;
      RECT 0.680 342.000 118.320 344.800 ;
      RECT 0.680 352.880 118.320 355.680 ;
      RECT 0.680 363.760 118.320 366.560 ;
      RECT 0.680 374.640 118.320 377.440 ;
      RECT 0.680 385.520 118.320 388.320 ;
      RECT 0.680 396.400 118.320 399.200 ;
      RECT 0.680 407.280 118.320 410.080 ;
      RECT 0.680 418.160 118.320 420.960 ;
      RECT 0.680 429.040 118.320 431.840 ;
      RECT 0.680 439.920 118.320 442.720 ;
      RECT 0.680 450.800 118.320 453.600 ;
      RECT 0.680 461.680 118.320 464.480 ;
      RECT 0.680 472.560 118.320 475.360 ;
      RECT 0.680 483.440 118.320 486.240 ;
      RECT 0.680 494.320 118.320 497.120 ;
      RECT 0.680 505.200 118.320 508.000 ;
      RECT 0.680 516.080 118.320 518.880 ;
      RECT 0.680 526.960 118.320 529.760 ;
      RECT 0.680 537.840 118.320 540.640 ;
      RECT 0.680 548.720 118.320 551.520 ;
      RECT 0.680 559.600 118.320 562.400 ;
      RECT 0.680 570.480 118.320 573.280 ;
      RECT 0.680 581.360 118.320 584.160 ;
      RECT 0.680 592.240 118.320 595.040 ;
      RECT 0.680 603.120 118.320 605.920 ;
      RECT 0.680 614.000 118.320 616.800 ;
      RECT 0.680 624.880 118.320 627.680 ;
      RECT 0.680 635.760 118.320 638.560 ;
      RECT 0.680 646.640 118.320 649.440 ;
      RECT 0.680 657.520 118.320 660.320 ;
      RECT 0.680 668.400 118.320 671.200 ;
      RECT 0.680 679.280 118.320 682.080 ;
      RECT 0.680 690.160 118.320 692.960 ;
      RECT 0.680 701.040 118.320 703.840 ;
      RECT 0.680 711.920 118.320 714.720 ;
      RECT 0.680 722.800 118.320 725.600 ;
      RECT 0.680 733.680 118.320 736.480 ;
      RECT 0.680 744.560 118.320 747.360 ;
      RECT 0.680 755.440 118.320 758.240 ;
      RECT 0.680 766.320 118.320 769.120 ;
      RECT 0.680 777.200 118.320 780.000 ;
      RECT 0.680 788.080 118.320 790.880 ;
      RECT 0.680 798.960 118.320 801.760 ;
      RECT 0.680 809.840 118.320 812.640 ;
      RECT 0.680 820.720 118.320 823.520 ;
      RECT 0.680 831.600 118.320 834.400 ;
      RECT 0.680 842.480 118.320 845.280 ;
      RECT 0.680 853.360 118.320 856.160 ;
      RECT 0.680 864.240 118.320 867.040 ;
      RECT 0.680 875.120 118.320 877.920 ;
      RECT 0.680 886.000 118.320 888.800 ;
      RECT 0.680 896.880 118.320 899.680 ;
      RECT 0.680 907.760 118.320 910.560 ;
      RECT 0.680 918.640 118.320 921.440 ;
      RECT 0.680 929.520 118.320 932.320 ;
      RECT 0.680 940.400 118.320 943.200 ;
      RECT 0.680 951.280 118.320 954.080 ;
      RECT 0.680 962.160 118.320 964.960 ;
      RECT 0.680 973.040 118.320 975.840 ;
      RECT 0.680 983.920 118.320 986.720 ;
      RECT 0.680 994.800 118.320 997.600 ;
      RECT 0.680 1005.680 118.320 1008.480 ;
      RECT 0.680 1016.560 118.320 1019.360 ;
      RECT 0.680 1027.440 118.320 1030.240 ;
      RECT 0.680 1038.320 118.320 1041.120 ;
      RECT 0.680 1049.200 118.320 1052.000 ;
      RECT 0.680 1060.080 118.320 1062.880 ;
      RECT 0.680 1070.960 118.320 1073.760 ;
      RECT 0.680 1081.840 118.320 1084.640 ;
      RECT 0.680 1092.720 118.320 1095.520 ;
      RECT 0.680 1103.600 118.320 1106.400 ;
      RECT 0.680 1114.480 118.320 1117.280 ;
      RECT 0.680 1125.360 118.320 1128.160 ;
      RECT 0.680 1136.240 118.320 1139.040 ;
      RECT 0.680 1147.120 118.320 1149.920 ;
      RECT 0.680 1158.000 118.320 1160.800 ;
      RECT 0.680 1168.880 118.320 1171.680 ;
      RECT 0.680 1179.760 118.320 1182.560 ;
      RECT 0.680 1190.640 118.320 1193.440 ;
      RECT 0.680 1201.520 118.320 1204.320 ;
      RECT 0.680 1212.400 118.320 1215.200 ;
      RECT 0.680 1223.280 118.320 1226.080 ;
      RECT 0.680 1234.160 118.320 1236.960 ;
      RECT 0.680 1245.040 118.320 1247.840 ;
      RECT 0.680 1255.920 118.320 1258.720 ;
      RECT 0.680 1266.800 118.320 1269.600 ;
      RECT 0.680 1277.680 118.320 1280.480 ;
      RECT 0.680 1288.560 118.320 1291.360 ;
      RECT 0.680 1299.440 118.320 1302.240 ;
      RECT 0.680 1310.320 118.320 1313.120 ;
      RECT 0.680 1321.200 118.320 1324.000 ;
      RECT 0.680 1332.080 118.320 1334.880 ;
      RECT 0.680 1342.960 118.320 1345.760 ;
      RECT 0.680 1353.840 118.320 1356.640 ;
      RECT 0.680 1364.720 118.320 1367.520 ;
      RECT 0.680 1375.600 118.320 1378.400 ;
      RECT 0.680 1386.480 118.320 1389.280 ;
      RECT 0.680 1397.360 118.320 1400.160 ;
      RECT 0.680 1408.240 118.320 1411.040 ;
      RECT 0.680 1419.120 118.320 1421.920 ;
      RECT 0.680 1430.000 118.320 1432.800 ;
      RECT 0.680 1440.880 118.320 1443.680 ;
      RECT 0.680 1451.760 118.320 1454.560 ;
      RECT 0.680 1462.640 118.320 1465.440 ;
      RECT 0.680 1473.520 118.320 1476.320 ;
      RECT 0.680 1484.400 118.320 1487.200 ;
      RECT 0.680 1495.280 118.320 1498.080 ;
      RECT 0.680 1506.160 118.320 1508.960 ;
      RECT 0.680 1517.040 118.320 1519.840 ;
      RECT 0.680 1527.920 118.320 1530.720 ;
      RECT 0.680 1538.800 118.320 1541.600 ;
      RECT 0.680 1549.680 118.320 1552.480 ;
      RECT 0.680 1560.560 118.320 1563.360 ;
      RECT 0.680 1571.440 118.320 1574.240 ;
      RECT 0.680 1582.320 118.320 1585.120 ;
      RECT 0.680 1593.200 118.320 1596.000 ;
      RECT 0.680 1604.080 118.320 1606.880 ;
      RECT 0.680 1614.960 118.320 1617.760 ;
      RECT 0.680 1625.840 118.320 1628.640 ;
      RECT 0.680 1636.720 118.320 1639.520 ;
      RECT 0.680 1647.600 118.320 1650.400 ;
      RECT 0.680 1658.480 118.320 1661.280 ;
      RECT 0.680 1669.360 118.320 1672.160 ;
      RECT 0.680 1680.240 118.320 1683.040 ;
      RECT 0.680 1691.120 118.320 1693.920 ;
      RECT 0.680 1702.000 118.320 1704.800 ;
      RECT 0.680 1712.880 118.320 1715.680 ;
      RECT 0.680 1723.760 118.320 1726.560 ;
      RECT 0.680 1734.640 118.320 1737.440 ;
      RECT 0.680 1745.520 118.320 1748.320 ;
      RECT 0.680 1756.400 118.320 1759.200 ;
      RECT 0.680 1767.280 118.320 1770.080 ;
      RECT 0.680 1778.160 118.320 1780.960 ;
      RECT 0.680 1789.040 118.320 1791.840 ;
      RECT 0.680 1799.920 118.320 1802.720 ;
      RECT 0.680 1810.800 118.320 1813.600 ;
      RECT 0.680 1821.680 118.320 1824.480 ;
      RECT 0.680 1832.560 118.320 1835.360 ;
      RECT 0.680 1843.440 118.320 1846.240 ;
      RECT 0.680 1854.320 118.320 1857.120 ;
      RECT 0.680 1865.200 118.320 1868.000 ;
      RECT 0.680 1876.080 118.320 1878.880 ;
      RECT 0.680 1886.960 118.320 1889.760 ;
      RECT 0.680 1897.840 118.320 1900.640 ;
      RECT 0.680 1908.720 118.320 1911.520 ;
      RECT 0.680 1919.600 118.320 1922.400 ;
      RECT 0.680 1930.480 118.320 1933.280 ;
      RECT 0.680 1941.360 118.320 1944.160 ;
      RECT 0.680 1952.240 118.320 1955.040 ;
      RECT 0.680 1963.120 118.320 1965.920 ;
      RECT 0.680 1974.000 118.320 1976.800 ;
      RECT 0.680 1984.880 118.320 1987.680 ;
      RECT 0.680 1995.760 118.320 1998.560 ;
      RECT 0.680 2006.640 118.320 2009.440 ;
      RECT 0.680 2017.520 118.320 2020.320 ;
      RECT 0.680 2028.400 118.320 2031.200 ;
      RECT 0.680 2039.280 118.320 2042.080 ;
      RECT 0.680 2050.160 118.320 2052.960 ;
      RECT 0.680 2061.040 118.320 2063.840 ;
      RECT 0.680 2071.920 118.320 2074.720 ;
      RECT 0.680 2082.800 118.320 2085.600 ;
      RECT 0.680 2093.680 118.320 2096.480 ;
      RECT 0.680 2104.560 118.320 2107.360 ;
      RECT 0.680 2115.440 118.320 2118.240 ;
      RECT 0.680 2126.320 118.320 2129.120 ;
      RECT 0.680 2137.200 118.320 2140.000 ;
      RECT 0.680 2148.080 118.320 2150.880 ;
      RECT 0.680 2158.960 118.320 2161.760 ;
      RECT 0.680 2169.840 118.320 2172.640 ;
      RECT 0.680 2180.720 118.320 2183.520 ;
      RECT 0.680 2191.600 118.320 2194.400 ;
      RECT 0.680 2202.480 118.320 2205.280 ;
      RECT 0.680 2213.360 118.320 2216.160 ;
      RECT 0.680 2224.240 118.320 2227.040 ;
      RECT 0.680 2235.120 118.320 2237.920 ;
      RECT 0.680 2246.000 118.320 2248.800 ;
      RECT 0.680 2256.880 118.320 2259.680 ;
      RECT 0.680 2267.760 118.320 2270.560 ;
      RECT 0.680 2278.640 118.320 2281.440 ;
      RECT 0.680 2289.520 118.320 2292.320 ;
      RECT 0.680 2300.400 118.320 2303.200 ;
      RECT 0.680 2311.280 118.320 2314.080 ;
      RECT 0.680 2322.160 118.320 2324.960 ;
      RECT 0.680 2333.040 118.320 2335.840 ;
      RECT 0.680 2343.920 118.320 2346.720 ;
      RECT 0.680 2354.800 118.320 2357.600 ;
    END
  END VDD
  OBS
    LAYER met1 ;
    RECT 0 0 119.000 2366.000 ;
    LAYER met2 ;
    RECT 0 0 119.000 2366.000 ;
  END
END fakeram_64x256
END LIBRARY
